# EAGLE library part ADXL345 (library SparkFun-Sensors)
3-axis SPI/I2C 2/4/8/16g accelerometer

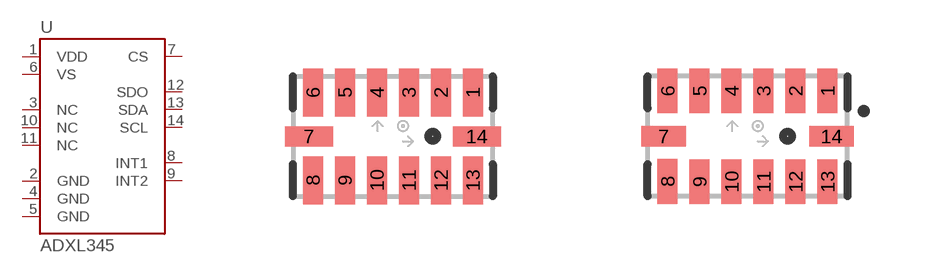
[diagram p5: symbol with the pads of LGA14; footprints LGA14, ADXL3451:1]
Designator prefix U

## ADXL345  [LGA14]
1  VDD
2  GND
3  NC
4  GND
5  GND
6  VS
7  CS
8  INT1
9  INT2
10  NC
11  NC
12  SDO
13  SDA
14  SCL

## ADXL345" (PROD_ID: IC-09097)  [ADXL3451:1]
Pads as for LGA14

## Footprint LGA14 (pad centres in mm)
smd 0.5 x 1.2: 1 2,1.1; 2 1.2,1.1; 3 0.4,1.1; 4 -0.4,1.1; 5 -1.2,1.1; 6 -2,1.1; 8 -2,-1.1; 9 -1.2,-1.1; 10 -0.4,-1.1; 11 0.4,-1.1; 12 1.2,-1.1; 13 2,-1.1
smd 1.2 x 0.5: 7 -2.1,0; 14 2.1,0

## Footprint ADXL3451:1 (pad centres in mm)
smd 0.5 x 1.124: 1 2,1.138; 2 1.2,1.138; 3 0.4,1.138; 4 -0.4,1.138; 5 -1.2,1.138; 6 -2,1.138; 8 -2,-1.13; 9 -1.2,-1.138; 10 -0.4,-1.138; 11 0.4,-1.138; 12 1.2,-1.138; 13 2,-1.138
smd 1.124 x 0.5: 7 -2.1,0; 14 2.1,0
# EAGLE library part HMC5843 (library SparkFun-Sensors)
Honeywell 3-axis digital compass IC, SEN-09371

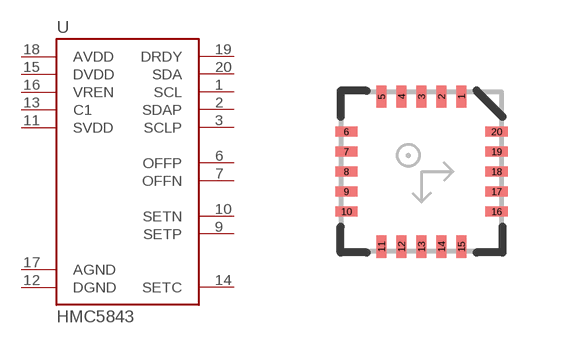
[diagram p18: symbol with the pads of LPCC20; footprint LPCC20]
Designator prefix U

## HMC5843SMD  [LPCC20]
1  SCL
2  SDAP
3  SCLP
6  OFFP
7  OFFN
9  SETP
10  SETN
11  SVDD
12  DGND
13  C1
14  SETC
15  DVDD
16  VREN
17  AGND
18  AVDD
19  DRDY
20  SDA

## Footprint LPCC20 (pad centres in mm)
smd 0.25 x 0.56: 1 1,1.88; 2 0.5,1.88; 3 0,1.88; 4 -0.5,1.88; 5 -1,1.88; 11 -1,-1.88; 12 -0.5,-1.88; 13 0,-1.88; 14 0.5,-1.88; 15 1,-1.88
smd 0.56 x 0.25: 6 -1.88,1; 7 -1.88,0.5; 8 -1.88,0; 9 -1.88,-0.5; 10 -1.88,-1; 16 1.88,-1; 17 1.88,-0.5; 18 1.88,0; 19 1.88,0.5; 20 1.88,1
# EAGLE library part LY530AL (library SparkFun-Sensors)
Single-axis 300deg/s gyro w/available 4x amplified output

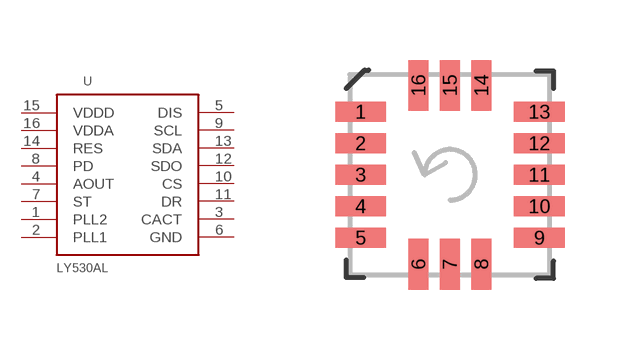
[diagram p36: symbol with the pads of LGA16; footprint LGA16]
Designator prefix -

## LY530ALSMD  [LGA16]
1  PLL2
2  PLL1
3  CACT
4  AOUT
5  DIS
6  GND
7  ST
8  PD
9  SCL
10  CS
11  DR
12  SDO
13  SDA
14  RES
15  VDDD
16  VDDA

## Footprint LGA16 (pad centres in mm)
LGA16 for LY530AL
smd 1.27 x 0.508: 1 -2.235,1.575; 2 -2.235,0.787; 3 -2.235,0; 4 -2.235,-0.787; 5 -2.235,-1.575; 9 2.235,-1.575; 10 2.235,-0.787; 11 2.235,0; 12 2.235,0.787; 13 2.235,1.575
smd 0.508 x 1.27: 6 -0.787,-2.235; 7 0,-2.235; 8 0.787,-2.235; 14 0.787,2.235; 15 0,2.235; 16 -0.787,2.235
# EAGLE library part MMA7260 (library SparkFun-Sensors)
Freescale 3-axis 1.5/2/4/6g analog output accelerometer. Schematic element and footprint production proven. Center pad has reduced paste layer for solder short reduction. Spark Fun Electronics SKU : COM-00308

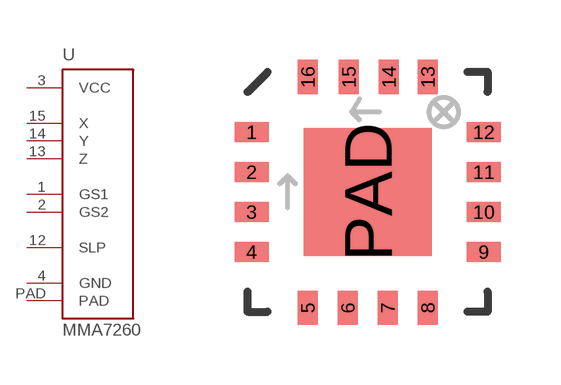
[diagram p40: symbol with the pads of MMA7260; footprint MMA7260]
Designator prefix U

## MMA7260  [MMA7260]
1  GS1
2  GS2
3  VCC
4  GND
12  SLP
13  Z
14  Y
15  X
PAD  PAD

## Footprint MMA7260 (pad centres in mm)
smd 0.855 x 0.5: 1 -2.902,1.5; 2 -2.902,0.5; 3 -2.902,-0.5; 4 -2.902,-1.5; 9 2.902,-1.5; 10 2.902,-0.5; 11 2.902,0.5; 12 2.902,1.5
smd 0.5 x 0.855: 5 -1.5,-2.902; 6 -0.5,-2.902; 7 0.5,-2.902; 8 1.5,-2.902; 13 1.5,2.877; 14 0.525,2.877; 15 -0.475,2.877; 16 -1.5,2.877
smd 3.2 x 3.2: PAD 0,0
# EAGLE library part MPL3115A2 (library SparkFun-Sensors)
Altimeter/Pressure Sensor, I2C, 1.95V-3.6V supply, 50 to 110kPa

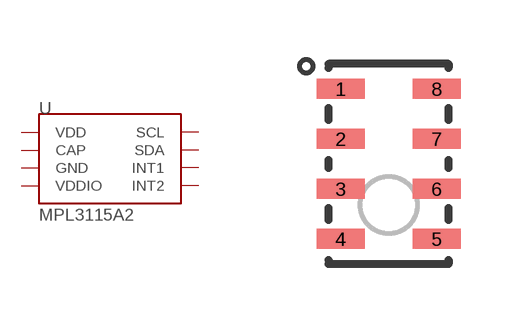
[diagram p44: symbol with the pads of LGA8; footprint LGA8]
Designator prefix U

## MPL3115A2LGA8 (PROD_ID: IC-10869)  [LGA8]
1  VDD  pwr
2  CAP  pwr
3  GND  pwr
4  VDDIO  pwr
5  INT2  out
6  INT1  out
7  SDA
8  SCL

## Footprint LGA8 (pad centres in mm)
LGA8 Package 5.0x3.0x1.2mm 8-pad Used in MPL115A1 -
smd 1.2 x 0.5: 1 -1.2,1.875; 2 -1.2,0.625; 3 -1.2,-0.625; 4 -1.2,-1.875; 5 1.2,-1.875; 6 1.2,-0.625; 7 1.2,0.625; 8 1.2,1.875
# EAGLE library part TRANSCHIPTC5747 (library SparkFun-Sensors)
CMOS image sensor

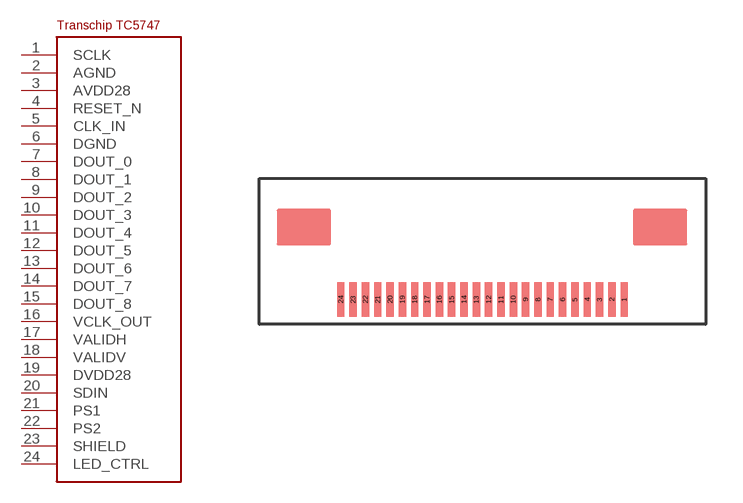
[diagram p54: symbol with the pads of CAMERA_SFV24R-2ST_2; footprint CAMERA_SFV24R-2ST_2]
Designator prefix -

## TRANSCHIPTC5747  [CAMERA_SFV24R-2ST_2]
1  SCLK
2  AGND
3  AVDD28
4  RESET_N
5  CLK_IN
6  DGND
7  DOUT_0
8  DOUT_1
9  DOUT_2
10  DOUT_3
11  DOUT_4
12  DOUT_5
13  DOUT_6
14  DOUT_7
15  DOUT_8
16  VCLK_OUT
17  VALIDH
18  VALIDV
19  DVDD28
20  SDIN
21  PS1
22  PS2
23  SHIELD
24  LED_CTRL

## Footprint CAMERA_SFV24R-2ST_2 (pad centres in mm)
smd 0.3 x 1.4: 1 5.08,-1.27; 2 4.58,-1.27; 3 4.08,-1.27; 4 3.58,-1.27; 5 3.08,-1.27; 6 2.58,-1.27; 7 2.08,-1.27; 8 1.58,-1.27; 9 1.08,-1.27; 10 0.58,-1.27; 11 0.08,-1.27; 12 -0.42,-1.27; 13 -0.92,-1.27; 14 -1.42,-1.27; 15 -1.92,-1.27; 16 -2.42,-1.27; 17 -2.92,-1.27; 18 -3.42,-1.27; 19 -3.92,-1.27; 20 -4.42,-1.27; 21 -4.92,-1.27; 22 -5.42,-1.27; 23 -5.92,-1.27; 24 -6.42,-1.27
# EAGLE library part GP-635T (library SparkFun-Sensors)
Description: Footprint and symbol for the GP-635T GPS module. This is a very small, very accurate, low-cost GPS receiver. Footprint works with SKU GPS-00579. Use cable GPS-00574 or GPS-09123 to connect the receiver to this footprint+connector.

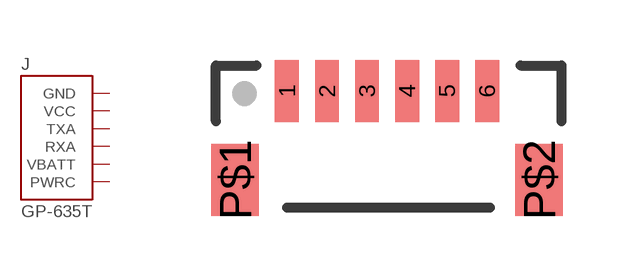
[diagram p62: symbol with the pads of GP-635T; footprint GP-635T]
Designator prefix J

## GP-635TSMD  [GP-635T]
1  GND  pwr
2  VCC  pwr
3  TXA  out
4  RXA  in
5  VBATT  pwr
6  PWRC  in

## Footprint GP-635T (pad centres in mm)
smd 0.6 x 1.55: 1 -2.54,1.27; 2 -1.54,1.27; 3 -0.54,1.27; 4 0.46,1.27; 5 1.46,1.27; 6 2.46,1.27
smd 1.2 x 1.8: P$1 -3.84,-0.955; P$2 3.76,-0.955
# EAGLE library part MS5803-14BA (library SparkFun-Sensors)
Measurement Specialties MS5803_14BA Pressure (Depth) Sensor Datasheet: https://cdn.sparkfun.com/datasheets/Sensors/Weather/ms5803_14ba.pdf

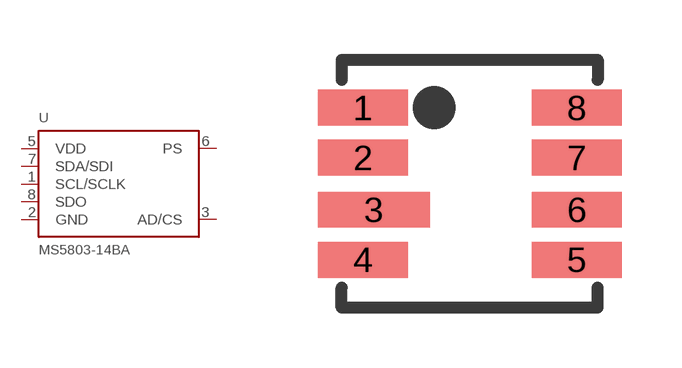
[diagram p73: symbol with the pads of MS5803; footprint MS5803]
Designator prefix U

## MS5803-14BA (PROD_ID: IC-12111)  [MS5803]
1  SCL/SCLK
2  GND
3  AD/CS
5  VDD
6  PS
7  SDA/SDI
8  SDO

## Footprint MS5803 (pad centres in mm)
smd 2.25 x 0.9: 1 -2.675,1.9; 2 -2.675,0.65; 4 -2.675,-1.9; 5 2.675,-1.9; 6 2.675,-0.65; 7 2.675,0.65; 8 2.675,1.9
smd 2.8 x 0.9: 3 -2.4,-0.65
